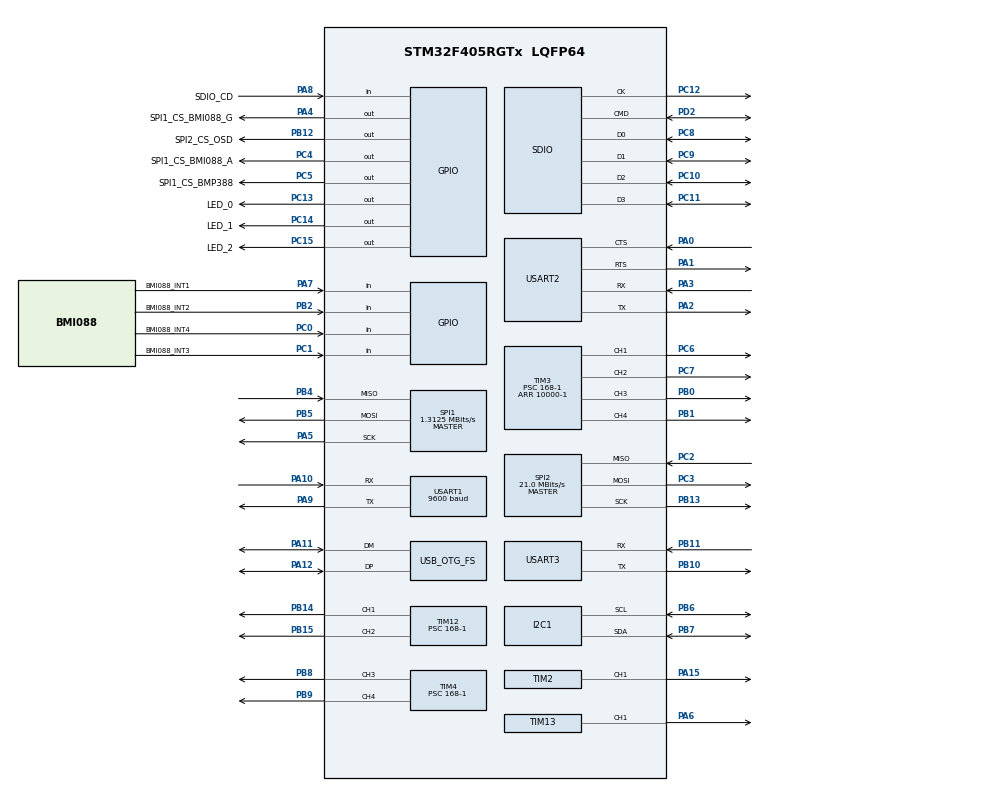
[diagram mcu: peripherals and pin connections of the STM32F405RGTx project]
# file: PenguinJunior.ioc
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FATFS.BSP.number=1
FATFS.USE_DMA_CODE_SD=0
FATFS._FS_EXFAT=1
FATFS._MAX_SS=4096
FATFS._USE_LFN=1
FATFS0.BSP.STBoard=false
FATFS0.BSP.api=Unknown
FATFS0.BSP.instance=PA8
FATFS0.BSP.ip=GPIO
FATFS0.BSP.mode=Input
FATFS0.BSP.name=Detect_SDIO
FATFS0.BSP.solution=PA8
Mcu.Family=STM32F4
Mcu.Name=STM32F405RGTx
Mcu.Package=LQFP64
NVIC.PriorityGroup=NVIC_PRIORITYGROUP_4
NVIC.TIM5_IRQn=true\:0\:0\:false\:false\:true\:true\:true\:true
NVIC.TIM6_DAC_IRQn=true\:0\:0\:true\:false\:true\:true\:true\:true
NVIC.USART1_IRQn=true\:0\:0\:false\:false\:true\:true\:true\:true
PA0-WKUP.Mode=CTS_RTS
PA0-WKUP.Signal=USART2_CTS
PA1.Mode=CTS_RTS
PA1.Signal=USART2_RTS
PA10.Mode=Asynchronous
PA10.Signal=USART1_RX
PA11.Mode=Device_Only
PA11.Signal=USB_OTG_FS_DM
PA12.Mode=Device_Only
PA12.Signal=USB_OTG_FS_DP
PA13.Mode=Trace_Asynchronous_SW
PA13.Signal=SYS_JTMS-SWDIO
PA14.Mode=Trace_Asynchronous_SW
PA14.Signal=SYS_JTCK-SWCLK
PA15.Signal=S_TIM2_CH1_ETR
PA2.Mode=Asynchronous
PA2.Signal=USART2_TX
PA3.Mode=Asynchronous
PA3.Signal=USART2_RX
PA4.GPIO_Label=SPI1_CS_BMI088_G
PA4.Signal=GPIO_Output
PA5.Mode=Full_Duplex_Master
PA5.Signal=SPI1_SCK
PA6.Signal=S_TIM13_CH1
PA7.GPIO_Label=BMI088_INT1
PA7.Signal=GPIO_Input
PA8.GPIO_Label=SDIO_CD
PA8.Signal=GPIO_Input
PA9.Mode=Asynchronous
PA9.Signal=USART1_TX
PB0.Signal=S_TIM3_CH3
PB1.Signal=S_TIM3_CH4
PB10.Mode=Asynchronous
PB10.Signal=USART3_TX
PB11.Mode=Asynchronous
PB11.Signal=USART3_RX
PB12.GPIO_Label=SPI2_CS_OSD
PB12.Signal=GPIO_Output
PB13.Mode=Full_Duplex_Master
PB13.Signal=SPI2_SCK
PB14.Signal=S_TIM12_CH1
PB15.Signal=S_TIM12_CH2
PB2.GPIO_Label=BMI088_INT2
PB2.Signal=GPIO_Input
PB3.Mode=Trace_Asynchronous_SW
PB3.Signal=SYS_JTDO-SWO
PB4.Mode=Full_Duplex_Master
PB4.Signal=SPI1_MISO
PB5.Mode=Full_Duplex_Master
PB5.Signal=SPI1_MOSI
PB6.Mode=I2C
PB6.Signal=I2C1_SCL
PB7.Mode=I2C
PB7.Signal=I2C1_SDA
PB8.Signal=S_TIM4_CH3
PB9.Signal=S_TIM4_CH4
PC0.GPIO_Label=BMI088_INT4
PC0.Signal=GPIO_Input
PC1.GPIO_Label=BMI088_INT3
PC1.Signal=GPIO_Input
PC10.Mode=SD_4_bits_Wide_bus
PC10.Signal=SDIO_D2
PC11.Mode=SD_4_bits_Wide_bus
PC11.Signal=SDIO_D3
PC12.Mode=SD_4_bits_Wide_bus
PC12.Signal=SDIO_CK
PC13-ANTI_TAMP.GPIO_Label=LED_0
PC13-ANTI_TAMP.Signal=GPIO_Output
PC14-OSC32_IN.GPIO_Label=LED_1
PC14-OSC32_IN.Signal=GPIO_Output
PC15-OSC32_OUT.GPIO_Label=LED_2
PC15-OSC32_OUT.Signal=GPIO_Output
PC2.Mode=Full_Duplex_Master
PC2.Signal=SPI2_MISO
PC3.Mode=Full_Duplex_Master
PC3.Signal=SPI2_MOSI
PC4.GPIO_Label=SPI1_CS_BMI088_A
PC4.Signal=GPIO_Output
PC5.GPIO_Label=SPI1_CS_BMP388
PC5.Signal=GPIO_Output
PC6.Signal=S_TIM3_CH1
PC7.Signal=S_TIM3_CH2
PC8.Mode=SD_4_bits_Wide_bus
PC8.Signal=SDIO_D0
PC9.Mode=SD_4_bits_Wide_bus
PC9.Signal=SDIO_D1
PD2.Mode=SD_4_bits_Wide_bus
PD2.Signal=SDIO_CMD
PH0-OSC_IN.Mode=HSE-External-Oscillator
PH0-OSC_IN.Signal=RCC_OSC_IN
PH1-OSC_OUT.Mode=HSE-External-Oscillator
PH1-OSC_OUT.Signal=RCC_OSC_OUT
ProjectManager.HeapSize=0x200
ProjectManager.StackSize=0x400
ProjectManager.TargetToolchain=CMake
RCC.48MHZClocksFreq_Value=48000000
RCC.AHBFreq_Value=168000000
RCC.APB1CLKDivider=RCC_HCLK_DIV4
RCC.APB1Freq_Value=42000000
RCC.APB1TimFreq_Value=84000000
RCC.APB2CLKDivider=RCC_HCLK_DIV4
RCC.APB2Freq_Value=42000000
RCC.APB2TimFreq_Value=84000000
RCC.CortexFreq_Value=168000000
RCC.HCLKFreq_Value=168000000
RCC.HSE_VALUE=16000000
RCC.HSI_VALUE=16000000
RCC.LSE_VALUE=32768
RCC.PLLM=8
RCC.PLLN=168
RCC.PLLQ=7
RCC.SYSCLKFreq_VALUE=168000000
RCC.SYSCLKSource=RCC_SYSCLKSOURCE_PLLCLK
RCC.VCOOutputFreq_Value=336000000
SH.S_TIM12_CH1.0=TIM12_CH1,PWM Generation1 CH1
SH.S_TIM12_CH2.0=TIM12_CH2,PWM Generation2 CH2
SH.S_TIM13_CH1.0=TIM13_CH1,PWM Generation1 CH1
SH.S_TIM2_CH1_ETR.0=TIM2_CH1,PWM Generation1 CH1
SH.S_TIM3_CH1.0=TIM3_CH1,PWM Generation1 CH1
SH.S_TIM3_CH2.0=TIM3_CH2,PWM Generation2 CH2
SH.S_TIM3_CH3.0=TIM3_CH3,PWM Generation3 CH3
SH.S_TIM3_CH4.0=TIM3_CH4,PWM Generation4 CH4
SH.S_TIM4_CH3.0=TIM4_CH3,PWM Generation3 CH3
SH.S_TIM4_CH4.0=TIM4_CH4,PWM Generation4 CH4
SPI1.BaudRatePrescaler=SPI_BAUDRATEPRESCALER_32
SPI1.CalculateBaudRate=1.3125 MBits/s
SPI1.Direction=SPI_DIRECTION_2LINES
SPI1.Mode=SPI_MODE_MASTER
SPI1.VirtualType=VM_MASTER
SPI2.CalculateBaudRate=21.0 MBits/s
SPI2.Direction=SPI_DIRECTION_2LINES
SPI2.Mode=SPI_MODE_MASTER
SPI2.VirtualType=VM_MASTER
TIM12.Channel-PWM\ Generation1\ CH1=TIM_CHANNEL_1
TIM12.Channel-PWM\ Generation2\ CH2=TIM_CHANNEL_2
TIM12.Period=10000-1
TIM12.Prescaler=168-1
TIM13.Channel=TIM_CHANNEL_1
TIM13.Period=10000-1
TIM13.Prescaler=168-1
TIM2.Channel-PWM\ Generation1\ CH1=TIM_CHANNEL_1
TIM2.Period=10000-1
TIM2.Prescaler=168-1
TIM3.Channel-PWM\ Generation1\ CH1=TIM_CHANNEL_1
TIM3.Channel-PWM\ Generation2\ CH2=TIM_CHANNEL_2
TIM3.Channel-PWM\ Generation3\ CH3=TIM_CHANNEL_3
TIM3.Channel-PWM\ Generation4\ CH4=TIM_CHANNEL_4
TIM3.Period=10000-1
TIM3.Prescaler=168-1
TIM4.Channel-PWM\ Generation3\ CH3=TIM_CHANNEL_3
TIM4.Channel-PWM\ Generation4\ CH4=TIM_CHANNEL_4
TIM4.Period=10000-1
TIM4.Prescaler=168-1
TIM5.AutoReloadPreload=TIM_AUTORELOAD_PRELOAD_ENABLE
TIM5.Period=42000
TIM5.Prescaler=100
TIM6.AutoReloadPreload=TIM_AUTORELOAD_PRELOAD_ENABLE
TIM6.Period=8400
TIM6.Prescaler=100
USART1.BaudRate=9600
USART1.VirtualMode=VM_ASYNC
USART2.VirtualMode=VM_ASYNC
USART3.VirtualMode=VM_ASYNC
USB_OTG_FS.VirtualMode=Device_Only
VP_FATFS_VS_SDIO.Mode=SDIO
VP_TIM13_VS_ClockSourceINT.Mode=Enable_Timer
VP_TIM5_VS_ClockSourceINT.Mode=Internal
VP_TIM6_VS_ClockSourceINT.Mode=Enable_Timer
board=custom

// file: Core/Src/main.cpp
/* USER CODE BEGIN Header */
/**
 ******************************************************************************
 * @file           : main.c
 * @brief          : Main program body
 ******************************************************************************
 * @attention
 *
 * Copyright (c) 2024 STMicroelectronics.
 * All rights reserved.
 *
 * This software is licensed under terms that can be found in the LICENSE file
 * in the root directory of this software component.
 * If no LICENSE file comes with this software, it is provided AS-IS.
 *
 ******************************************************************************
 */
/* USER CODE END Header */
#include "main.h"

#include <stdint.h>

#include "fatfs.h"
#include "gpio.h"
#include "i2c.h"
#include "sdio.h"
#include "spi.h"
#include "stm32f4xx_hal.h"
#include "tim.h"
#include "usart.h"
#include "usb_otg.h"

/* USER CODE BEGIN Includes */
#include "example_class.hpp"
extern "C" {
#include "sd_file_handling.h"
}
#include "hcsr04.hpp"
#include "logger.hpp"

/* USER CODE END Includes */

/* USER CODE BEGIN PV */
ExampleClass exampleClass;

/* USER CODE END PV */

void SystemClock_Config(void);

int main(void) {

    /* MCU Configuration--------------------------------------------------------*/

    /* Reset of all peripherals, Initializes the Flash interface and the Systick.
     */
    HAL_Init();

    /* Configure the system clock */
    SystemClock_Config();

    /* Initialize all configured peripherals */
    MX_GPIO_Init();
    MX_I2C1_Init();
    MX_SDIO_SD_Init();
    MX_SPI1_Init();
    MX_SPI2_Init();
    MX_TIM2_Init();
    MX_TIM3_Init();
    MX_TIM4_Init();
    MX_TIM12_Init();
    MX_TIM13_Init();
    MX_USART1_UART_Init();
    MX_USART2_UART_Init();
    MX_USART3_UART_Init();
    MX_USB_OTG_FS_PCD_Init();
    MX_TIM5_Init();
    MX_TIM6_Init();
    MX_FATFS_Init();
    /* USER CODE BEGIN 2 */

    logger.Configure();
    exampleClass.Configure();
    exampleClass.EnableFilter();

    /* USER CODE END 2 */

    /* Infinite loop */
    while (1) {

        /* USER CODE BEGIN 3 */
        exampleClass.Update();
        logger.WriteCachedLines();
    }
    /* USER CODE END 3 */
}

void SystemClock_Config(void) {
    RCC_OscInitTypeDef RCC_OscInitStruct;
    RCC_ClkInitTypeDef RCC_ClkInitStruct;

    /** Configure the main internal regulator output voltage
     */
    __HAL_RCC_PWR_CLK_ENABLE();
    __HAL_PWR_VOLTAGESCALING_CONFIG(PWR_REGULATOR_VOLTAGE_SCALE1);

    /** Initializes the RCC Oscillators according to the specified parameters
     * in the RCC_OscInitTypeDef structure.
     */
    RCC_OscInitStruct.OscillatorType = RCC_OSCILLATORTYPE_HSE;
    RCC_OscInitStruct.HSEState = RCC_HSE_ON;
    RCC_OscInitStruct.PLL.PLLState = RCC_PLL_ON;
    RCC_OscInitStruct.PLL.PLLSource = RCC_PLLSOURCE_HSE;
    RCC_OscInitStruct.PLL.PLLM = 8;
    RCC_OscInitStruct.PLL.PLLN = 168;
    RCC_OscInitStruct.PLL.PLLP = RCC_PLLP_DIV2;
    RCC_OscInitStruct.PLL.PLLQ = 7;
    if (HAL_RCC_OscConfig(&RCC_OscInitStruct) != HAL_OK) {
        Error_Handler();
    }

    /** Initializes the CPU, AHB and APB buses clocks
     */
    RCC_ClkInitStruct.ClockType = RCC_CLOCKTYPE_HCLK | RCC_CLOCKTYPE_SYSCLK | RCC_CLOCKTYPE_PCLK1 | RCC_CLOCKTYPE_PCLK2;
    RCC_ClkInitStruct.SYSCLKSource = RCC_SYSCLKSOURCE_PLLCLK;
    RCC_ClkInitStruct.AHBCLKDivider = RCC_SYSCLK_DIV1;
    RCC_ClkInitStruct.APB1CLKDivider = RCC_HCLK_DIV4;
    RCC_ClkInitStruct.APB2CLKDivider = RCC_HCLK_DIV2;

    if (HAL_RCC_ClockConfig(&RCC_ClkInitStruct, FLASH_LATENCY_5) != HAL_OK) {
        Error_Handler();
    }
}

/* USER CODE BEGIN 4 */
void HAL_TIM_PeriodElapsedCallback(TIM_HandleTypeDef *htim) {
    if (htim->Instance == TIM5) {
        exampleClass.InterruptHandlerTim5();
    }

    else if (htim->Instance == TIM6) {
        exampleClass.InterruptHandlerTim6();
    }
}

void HAL_UART_RxCpltCallback(UART_HandleTypeDef *huart) {

}

/* USER CODE END 4 */

void Error_Handler(void) {
    __disable_irq();
    while (1) {
    }
}

#ifdef USE_FULL_ASSERT
/**
 * @brief  Reports the name of the source file and the source line number
 *         where the assert_param error has occurred.
 * @param  file: pointer to the source file name
 * @param  line: assert_param error line source number
 * @retval None
 */
void assert_failed(uint8_t *file, uint32_t line) {
    /* USER CODE BEGIN 6 */
    /* User can add his own implementation to report the file name and line
       number, ex: printf("Wrong parameters value: file %s on line %d\r\n", file,
       line) */
    /* USER CODE END 6 */
}
#endif /* USE_FULL_ASSERT */
